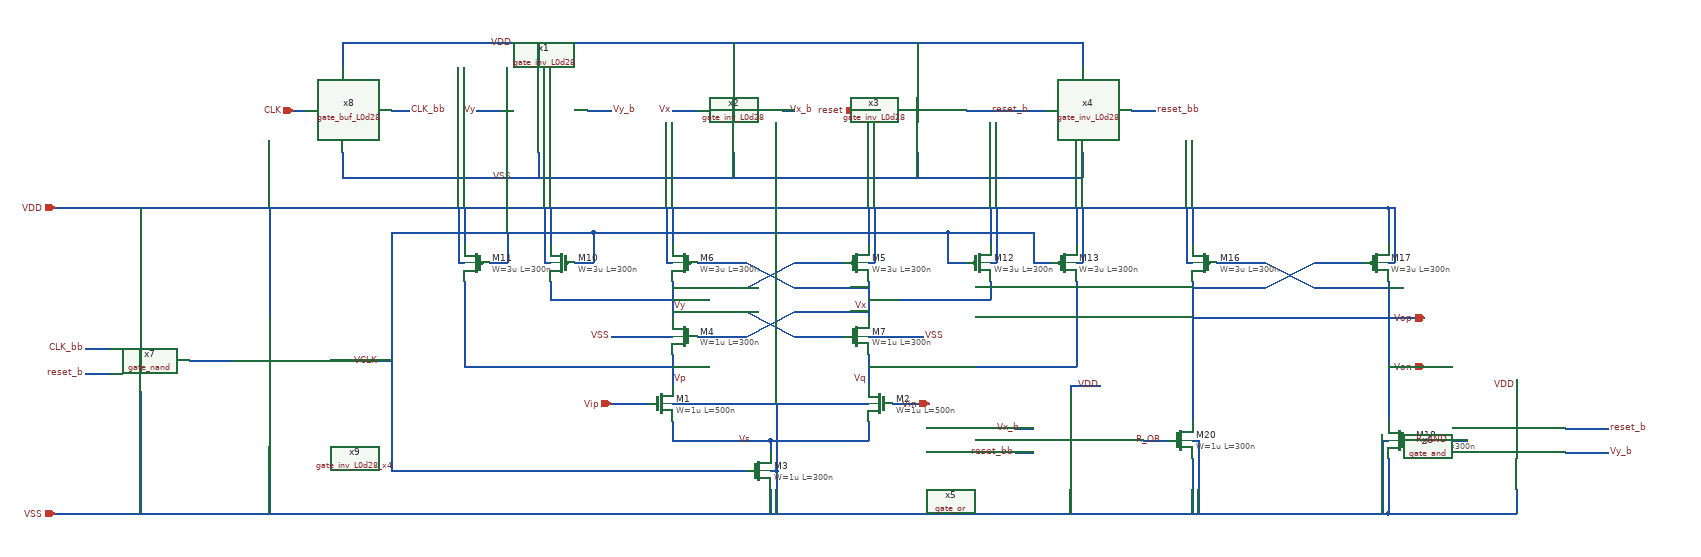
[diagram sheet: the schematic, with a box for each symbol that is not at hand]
v {xschem version=3.4.8RC file_version=1.3}
G {}
K {}
V {}
S {}
F {}
E {}
N 710 -190 710 -170 {lab=Vs}
N 710 -190 870 -190 {lab=Vs}
N 870 -220 870 -190 {lab=Vs}
N 550 -190 710 -190 {lab=Vs}
N 550 -220 550 -190 {lab=Vs}
N 710 -110 710 -70 {lab=VSS}
N 550 -250 870 -250 {lab=VSS}
N 720 -140 720 -70 {lab=VSS}
N 720 -250 720 -140 {lab=VSS}
N 550 -330 550 -280 {lab=Vp}
N 870 -330 870 -280 {lab=Vq}
N 870 -450 870 -390 {lab=Vx}
N 550 -450 550 -390 {lab=Vy}
N 590 -480 670 -480 {lab=Vx}
N 750 -480 830 -480 {lab=Vy}
N 590 -360 670 -360 {lab=Vx}
N 750 -360 830 -360 {lab=Vy}
N 670 -480 750 -440 {lab=Vx}
N 670 -440 750 -480 {lab=Vy}
N 670 -400 750 -360 {lab=Vy}
N 670 -360 750 -400 {lab=Vx}
N 550 -400 670 -400 {lab=Vy}
N 750 -400 870 -400 {lab=Vx}
N 750 -440 870 -440 {lab=Vx}
N 550 -440 670 -440 {lab=Vy}
N 550 -570 550 -510 {lab=VDD}
N 870 -570 870 -510 {lab=VDD}
N 210 -570 210 -510 {lab=VDD}
N 350 -570 350 -510 {lab=VDD}
N 350 -420 550 -420 {lab=Vy}
N 350 -450 350 -420 {lab=Vy}
N 210 -450 210 -310 {lab=Vp}
N 210 -310 550 -310 {lab=Vp}
N 870 -420 1070 -420 {lab=Vx}
N 1070 -570 1070 -510 {lab=VDD}
N 1070 -450 1070 -420 {lab=Vx}
N 200 -480 210 -480 {lab=VDD}
N 200 -570 200 -480 {lab=VDD}
N 340 -480 350 -480 {lab=VDD}
N 340 -570 340 -480 {lab=VDD}
N 540 -480 550 -480 {lab=VDD}
N 540 -570 540 -480 {lab=VDD}
N 870 -480 880 -480 {lab=VDD}
N 710 -140 720 -140 {lab=VSS}
N 870 -310 1210 -310 {lab=Vq}
N 1210 -570 1210 -510 {lab=VDD}
N 1070 -480 1080 -480 {lab=VDD}
N 1080 -570 1080 -480 {lab=VDD}
N 1210 -480 1220 -480 {lab=VDD}
N 1220 -570 1220 -480 {lab=VDD}
N 1210 -450 1210 -310 {lab=Vq}
N 1140 -480 1170 -480 {lab=VCLK}
N 1140 -530 1140 -480 {lab=VCLK}
N 1000 -480 1030 -480 {lab=VCLK}
N 1000 -530 1000 -480 {lab=VCLK}
N 390 -480 420 -480 {lab=VCLK}
N 420 -530 420 -480 {lab=VCLK}
N 250 -480 280 -480 {lab=VCLK}
N 280 -530 280 -480 {lab=VCLK}
N 450 -250 510 -250 {lab=Vip}
N 910 -250 970 -250 {lab=Vin}
N 90 -140 670 -140 {lab=VCLK}
N 1440 -480 1520 -480 {lab=Von}
N 1600 -480 1680 -480 {lab=Vop}
N 1520 -480 1600 -440 {lab=Von}
N 1520 -440 1600 -480 {lab=Vop}
N 1400 -570 1400 -510 {lab=VDD}
N 1720 -570 1720 -510 {lab=VDD}
N 1390 -570 1390 -480 {lab=VDD}
N 670 -570 1300 -570 {lab=VDD}
N 1400 -440 1520 -440 {lab=Vop}
N 1600 -440 1720 -440 {lab=Von}
N 680 -70 1300 -70 {lab=VSS}
N 1400 -190 1410 -190 {lab=VSS}
N 1400 -450 1400 -270 {lab=Vop}
N 1720 -450 1720 -270 {lab=Von}
N 1300 -70 1720 -70 {lab=VSS}
N 1300 -570 1720 -570 {lab=VDD}
N 1720 -480 1730 -480 {lab=VDD}
N 1730 -570 1730 -480 {lab=VDD}
N 1390 -480 1400 -480 {lab=VDD}
N 450 -360 550 -360 {lab=VSS}
N 870 -360 960 -360 {lab=VSS}
N 880 -570 880 -480 {lab=VDD}
N 1400 -390 1780 -390 {lab=Vop}
N 1720 -310 1780 -310 {lab=Von}
N 150 -570 670 -570 {lab=VDD}
N 150 -70 680 -70 {lab=VSS}
N 550 -730 590 -730 {lab=Vx}
N 850 -730 890 -730 {lab=reset}
N 1120 -730 1160 -730 {lab=reset_b}
N 1300 -730 1340 -730 {lab=reset_bb}
N 650 -660 650 -620 {lab=VSS}
N 650 -840 650 -800 {lab=VDD}
N 410 -730 450 -730 {lab=Vy_b}
N 330 -660 330 -620 {lab=VSS}
N 330 -840 330 -800 {lab=VDD}
N 230 -730 270 -730 {lab=Vy}
N 950 -660 950 -620 {lab=VSS}
N 1220 -660 1220 -620 {lab=VSS}
N 1220 -840 1220 -800 {lab=VDD}
N 950 -840 950 -800 {lab=VDD}
N 290 -620 1130 -620 {lab=VSS}
N 290 -840 1130 -840 {lab=VDD}
N 1720 -570 1730 -570 {lab=VDD}
N 2010 -210 2080 -210 {lab=reset_b}
N 2010 -170 2080 -170 {lab=Vy_b}
N 1110 -210 1140 -210 {lab=Vx_b}
N 1110 -170 1140 -170 {lab=reset_bb}
N 1200 -280 1250 -280 {lab=VDD}
N 1200 -110 1200 -80 {lab=VSS}
N 1200 -80 1200 -70 {lab=VSS}
N 1760 -190 1850 -190 {lab=#net1}
N 1720 -270 1720 -220 {lab=Von}
N 1720 -160 1720 -70 {lab=VSS}
N 1710 -190 1720 -190 {lab=VSS}
N 1710 -190 1710 -70 {lab=VSS}
N 1400 -160 1400 -70 {lab=VSS}
N 1410 -190 1410 -70 {lab=VSS}
N 1320 -190 1360 -190 {lab=VDD}
N 1400 -270 1400 -220 {lab=Vop}
N 1930 -290 1930 -270 {lab=VDD}
N 1930 -110 1930 -70 {lab=VSS}
N 1720 -70 1930 -70 {lab=VSS}
N 730 -730 750 -730 {lab=Vx_b}
N 1200 -280 1200 -270 {lab=VDD}
N 1030 -730 1120 -730 {lab=reset_b}
N 1130 -840 1220 -840 {lab=VDD}
N 1130 -620 1220 -620 {lab=VSS}
N 1000 -530 1140 -530 {lab=VCLK}
N 420 -530 1000 -530 {lab=VCLK}
N 270 -530 420 -530 {lab=VCLK}
N 90 -530 270 -530 {lab=VCLK}
N 90 -530 90 -140 {lab=VCLK}
N 40 -320 90 -320 {lab=VCLK}
N -70 -730 -50 -730 {lab=CLK}
N 90 -730 120 -730 {lab=CLK_bb}
N 10 -840 290 -840 {lab=VDD}
N 10 -840 10 -800 {lab=VDD}
N 10 -660 10 -620 {lab=VSS}
N 10 -620 330 -620 {lab=VSS}
N -410 -340 -380 -340 {lab=CLK_bb}
N -410 -300 -380 -300 {lab=reset_b}
N -460 -570 150 -570 {lab=VDD}
N -460 -70 150 -70 {lab=VSS}
N -320 -570 -320 -400 {lab=VDD}
N -30 -320 40 -320 {lab=VCLK}
N -200 -320 -170 -320 {lab=#net2}
N -110 -570 -110 -390 {lab=VDD}
N -110 -250 -110 -70 {lab=VSS}
N -320 -400 -320 -370 {lab=VDD}
N -240 -320 -200 -320 {lab=#net2}
N -380 -300 -370 -300 {lab=reset_b}
N -380 -340 -370 -340 {lab=CLK_bb}
N -320 -270 -320 -70 {lab=VSS}
C {symbols/nfet_03v3.sym} 530 -250 0 0 {name=M1
L=500n
W=1u
nf=1
m=20
ad="'int((nf+1)/2) * W/nf * 0.18u'"
pd="'2*int((nf+1)/2) * (W/nf + 0.18u)'"
as="'int((nf+2)/2) * W/nf * 0.18u'"
ps="'2*int((nf+2)/2) * (W/nf + 0.18u)'"
nrd="'0.18u / W'" nrs="'0.18u / W'"
sa=0 sb=0 sd=0
model=nfet_03v3
spiceprefix=X
}
C {symbols/nfet_03v3.sym} 890 -250 0 1 {name=M2
L=500n
W=1u
nf=1
m=20
ad="'int((nf+1)/2) * W/nf * 0.18u'"
pd="'2*int((nf+1)/2) * (W/nf + 0.18u)'"
as="'int((nf+2)/2) * W/nf * 0.18u'"
ps="'2*int((nf+2)/2) * (W/nf + 0.18u)'"
nrd="'0.18u / W'" nrs="'0.18u / W'"
sa=0 sb=0 sd=0
model=nfet_03v3
spiceprefix=X
}
C {symbols/nfet_03v3.sym} 690 -140 0 0 {name=M3
L=300n
W=1u
nf=1
m=12
ad="'int((nf+1)/2) * W/nf * 0.18u'"
pd="'2*int((nf+1)/2) * (W/nf + 0.18u)'"
as="'int((nf+2)/2) * W/nf * 0.18u'"
ps="'2*int((nf+2)/2) * (W/nf + 0.18u)'"
nrd="'0.18u / W'" nrs="'0.18u / W'"
sa=0 sb=0 sd=0
model=nfet_03v3
spiceprefix=X
}
C {symbols/pfet_03v3.sym} 570 -480 0 1 {name=M6
L=300n
W=3u
nf=1
m=2
ad="'int((nf+1)/2) * W/nf * 0.18u'"
pd="'2*int((nf+1)/2) * (W/nf + 0.18u)'"
as="'int((nf+2)/2) * W/nf * 0.18u'"
ps="'2*int((nf+2)/2) * (W/nf + 0.18u)'"
nrd="'0.18u / W'" nrs="'0.18u / W'"
sa=0 sb=0 sd=0
model=pfet_03v3
spiceprefix=X
}
C {symbols/pfet_03v3.sym} 850 -480 0 0 {name=M5
L=300n
W=3u
nf=1
m=2
ad="'int((nf+1)/2) * W/nf * 0.18u'"
pd="'2*int((nf+1)/2) * (W/nf + 0.18u)'"
as="'int((nf+2)/2) * W/nf * 0.18u'"
ps="'2*int((nf+2)/2) * (W/nf + 0.18u)'"
nrd="'0.18u / W'" nrs="'0.18u / W'"
sa=0 sb=0 sd=0
model=pfet_03v3
spiceprefix=X
}
C {symbols/nfet_03v3.sym} 570 -360 0 1 {name=M4
L=300n
W=1u
nf=1
m=2
ad="'int((nf+1)/2) * W/nf * 0.18u'"
pd="'2*int((nf+1)/2) * (W/nf + 0.18u)'"
as="'int((nf+2)/2) * W/nf * 0.18u'"
ps="'2*int((nf+2)/2) * (W/nf + 0.18u)'"
nrd="'0.18u / W'" nrs="'0.18u / W'"
sa=0 sb=0 sd=0
model=nfet_03v3
spiceprefix=X
}
C {symbols/nfet_03v3.sym} 850 -360 0 0 {name=M7
L=300n
W=1u
nf=1
m=2
ad="'int((nf+1)/2) * W/nf * 0.18u'"
pd="'2*int((nf+1)/2) * (W/nf + 0.18u)'"
as="'int((nf+2)/2) * W/nf * 0.18u'"
ps="'2*int((nf+2)/2) * (W/nf + 0.18u)'"
nrd="'0.18u / W'" nrs="'0.18u / W'"
sa=0 sb=0 sd=0
model=nfet_03v3
spiceprefix=X
}
C {symbols/pfet_03v3.sym} 370 -480 0 1 {name=M10
L=300n
W=3u
nf=1
m=2
ad="'int((nf+1)/2) * W/nf * 0.18u'"
pd="'2*int((nf+1)/2) * (W/nf + 0.18u)'"
as="'int((nf+2)/2) * W/nf * 0.18u'"
ps="'2*int((nf+2)/2) * (W/nf + 0.18u)'"
nrd="'0.18u / W'" nrs="'0.18u / W'"
sa=0 sb=0 sd=0
model=pfet_03v3
spiceprefix=X
}
C {symbols/pfet_03v3.sym} 230 -480 0 1 {name=M11
L=300n
W=3u
nf=1
m=2
ad="'int((nf+1)/2) * W/nf * 0.18u'"
pd="'2*int((nf+1)/2) * (W/nf + 0.18u)'"
as="'int((nf+2)/2) * W/nf * 0.18u'"
ps="'2*int((nf+2)/2) * (W/nf + 0.18u)'"
nrd="'0.18u / W'" nrs="'0.18u / W'"
sa=0 sb=0 sd=0
model=pfet_03v3
spiceprefix=X
}
C {symbols/pfet_03v3.sym} 1050 -480 0 0 {name=M12
L=300n
W=3u
nf=1
m=2
ad="'int((nf+1)/2) * W/nf * 0.18u'"
pd="'2*int((nf+1)/2) * (W/nf + 0.18u)'"
as="'int((nf+2)/2) * W/nf * 0.18u'"
ps="'2*int((nf+2)/2) * (W/nf + 0.18u)'"
nrd="'0.18u / W'" nrs="'0.18u / W'"
sa=0 sb=0 sd=0
model=pfet_03v3
spiceprefix=X
}
C {symbols/pfet_03v3.sym} 1190 -480 0 0 {name=M13
L=300n
W=3u
nf=1
m=2
ad="'int((nf+1)/2) * W/nf * 0.18u'"
pd="'2*int((nf+1)/2) * (W/nf + 0.18u)'"
as="'int((nf+2)/2) * W/nf * 0.18u'"
ps="'2*int((nf+2)/2) * (W/nf + 0.18u)'"
nrd="'0.18u / W'" nrs="'0.18u / W'"
sa=0 sb=0 sd=0
model=pfet_03v3
spiceprefix=X
}
C {lab_wire.sym} 870 -290 0 0 {name=p1 sig_type=std_logic lab=Vq}
C {lab_wire.sym} 550 -290 0 1 {name=p2 sig_type=std_logic lab=Vp}
C {lab_wire.sym} 680 -190 0 0 {name=p3 sig_type=std_logic lab=Vs}
C {lab_wire.sym} 550 -410 0 1 {name=p4 sig_type=std_logic lab=Vy}
C {lab_wire.sym} 870 -410 0 0 {name=p5 sig_type=std_logic lab=Vx}
C {symbols/pfet_03v3.sym} 1420 -480 0 1 {name=M16
L=300n
W=3u
nf=1
m=2
ad="'int((nf+1)/2) * W/nf * 0.18u'"
pd="'2*int((nf+1)/2) * (W/nf + 0.18u)'"
as="'int((nf+2)/2) * W/nf * 0.18u'"
ps="'2*int((nf+2)/2) * (W/nf + 0.18u)'"
nrd="'0.18u / W'" nrs="'0.18u / W'"
sa=0 sb=0 sd=0
model=pfet_03v3
spiceprefix=X
}
C {symbols/pfet_03v3.sym} 1700 -480 0 0 {name=M17
L=300n
W=3u
nf=1
m=2
ad="'int((nf+1)/2) * W/nf * 0.18u'"
pd="'2*int((nf+1)/2) * (W/nf + 0.18u)'"
as="'int((nf+2)/2) * W/nf * 0.18u'"
ps="'2*int((nf+2)/2) * (W/nf + 0.18u)'"
nrd="'0.18u / W'" nrs="'0.18u / W'"
sa=0 sb=0 sd=0
model=pfet_03v3
spiceprefix=X
}
C {symbols/nfet_03v3.sym} 1740 -190 0 1 {name=M18
L=300n
W=1u
nf=1
m=4
ad="'int((nf+1)/2) * W/nf * 0.18u'"
pd="'2*int((nf+1)/2) * (W/nf + 0.18u)'"
as="'int((nf+2)/2) * W/nf * 0.18u'"
ps="'2*int((nf+2)/2) * (W/nf + 0.18u)'"
nrd="'0.18u / W'" nrs="'0.18u / W'"
sa=0 sb=0 sd=0
model=nfet_03v3
spiceprefix=X
}
C {symbols/nfet_03v3.sym} 1380 -190 0 0 {name=M20
L=300n
W=1u
nf=1
m=4
ad="'int((nf+1)/2) * W/nf * 0.18u'"
pd="'2*int((nf+1)/2) * (W/nf + 0.18u)'"
as="'int((nf+2)/2) * W/nf * 0.18u'"
ps="'2*int((nf+2)/2) * (W/nf + 0.18u)'"
nrd="'0.18u / W'" nrs="'0.18u / W'"
sa=0 sb=0 sd=0
model=nfet_03v3
spiceprefix=X
}
C {ipin.sym} 450 -250 0 0 {name=p16 lab=Vip}
C {ipin.sym} 970 -250 2 0 {name=p17 lab=Vin}
C {ipin.sym} -70 -730 0 0 {name=p18 lab=CLK}
C {iopin.sym} -460 -570 2 0 {name=p20 lab=VDD}
C {iopin.sym} -460 -70 2 0 {name=p21 lab=VSS}
C {iopin.sym} 1780 -390 0 0 {name=p22 lab=Vop}
C {iopin.sym} 1780 -310 0 0 {name=p23 lab=Von}
C {lab_wire.sym} 450 -360 0 0 {name=p24 sig_type=std_logic lab=VSS}
C {lab_wire.sym} 960 -360 0 1 {name=p25 sig_type=std_logic lab=VSS}
C {lab_wire.sym} 230 -730 0 0 {name=p6 sig_type=std_logic lab=Vy}
C {lab_wire.sym} 550 -730 0 0 {name=p7 sig_type=std_logic lab=Vx}
C {lab_wire.sym} 740 -730 0 1 {name=p8 sig_type=std_logic lab=Vx_b}
C {lab_wire.sym} 450 -730 0 1 {name=p9 sig_type=std_logic lab=Vy_b}
C {lab_wire.sym} 1340 -730 0 1 {name=p10 sig_type=std_logic lab=reset_bb}
C {ipin.sym} 850 -730 0 0 {name=p11 lab=reset}
C {lab_wire.sym} 1070 -730 0 1 {name=p19 sig_type=std_logic lab=reset_b}
C {lab_wire.sym} 290 -840 0 0 {name=p26 sig_type=std_logic lab=VDD}
C {lab_wire.sym} 290 -620 0 0 {name=p27 sig_type=std_logic lab=VSS}
C {DS_modulator/gate_or/xschem/gate_or.sym} 1220 -190 0 0 {name=x5}
C {DS_modulator/gate_and/xschem/gate_and.sym} 1930 -190 0 1 {name=x6}
C {lab_wire.sym} 2080 -210 0 1 {name=p28 sig_type=std_logic lab=reset_b}
C {lab_wire.sym} 2080 -170 0 1 {name=p29 sig_type=std_logic lab=Vy_b}
C {lab_wire.sym} 1110 -170 0 0 {name=p14 sig_type=std_logic lab=reset_bb}
C {lab_wire.sym} 1120 -210 0 0 {name=p30 sig_type=std_logic lab=Vx_b}
C {lab_wire.sym} 1250 -280 0 0 {name=p12 sig_type=std_logic lab=VDD}
C {lab_wire.sym} 1930 -280 0 0 {name=p13 sig_type=std_logic lab=VDD}
C {DS_modulator/gate_inv_L0d28/xschem/gate_inv_L0d28.sym} 330 -730 0 0 {name=x1}
C {DS_modulator/gate_inv_L0d28/xschem/gate_inv_L0d28.sym} 650 -730 0 0 {name=x2}
C {DS_modulator/gate_inv_L0d28/xschem/gate_inv_L0d28.sym} 950 -730 0 0 {name=x3}
C {DS_modulator/gate_inv_L0d28/xschem/gate_inv_L0d28.sym} 1220 -730 0 0 {name=x4}
C {DS_modulator/gate_buf_L0d28/xschem/gate_buf_L0d28.sym} 10 -730 0 0 {name=x8}
C {lab_wire.sym} 120 -730 0 1 {name=p15 sig_type=std_logic lab=CLK_bb}
C {lab_wire.sym} -410 -340 0 0 {name=p31 sig_type=std_logic lab=CLK_bb}
C {lab_wire.sym} -410 -300 0 0 {name=p32 sig_type=std_logic lab=reset_b}
C {DS_modulator/gate_inv_L0d28_x4/xschem/gate_inv_L0d28_x4.sym} -110 -320 0 0 {name=x9}
C {lab_wire.sym} 70 -320 0 0 {name=p33 sig_type=std_logic lab=VCLK}
C {DS_modulator/gate_nand/xscheme/gate_nand.sym} -320 -320 0 0 {name=x7}
C {lab_wire.sym} 1350 -190 0 0 {name=p34 sig_type=std_logic lab=R_OR}
C {lab_wire.sym} 1820 -190 0 0 {name=p35 sig_type=std_logic lab=R_AND}
